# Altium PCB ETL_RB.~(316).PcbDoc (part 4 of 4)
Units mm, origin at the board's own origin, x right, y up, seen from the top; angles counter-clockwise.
Board outline 130.3 x 56.5 mm, 8 copper layers (Top Layer, plane 1, M1, plane 2, plane 3, M2, plane 4, Bottom Layer), stack 0.972 mm thick; 202 components, 189 nets, 1825 pads, 884 vias.
Unrouted connection lines stored in the file: 411.

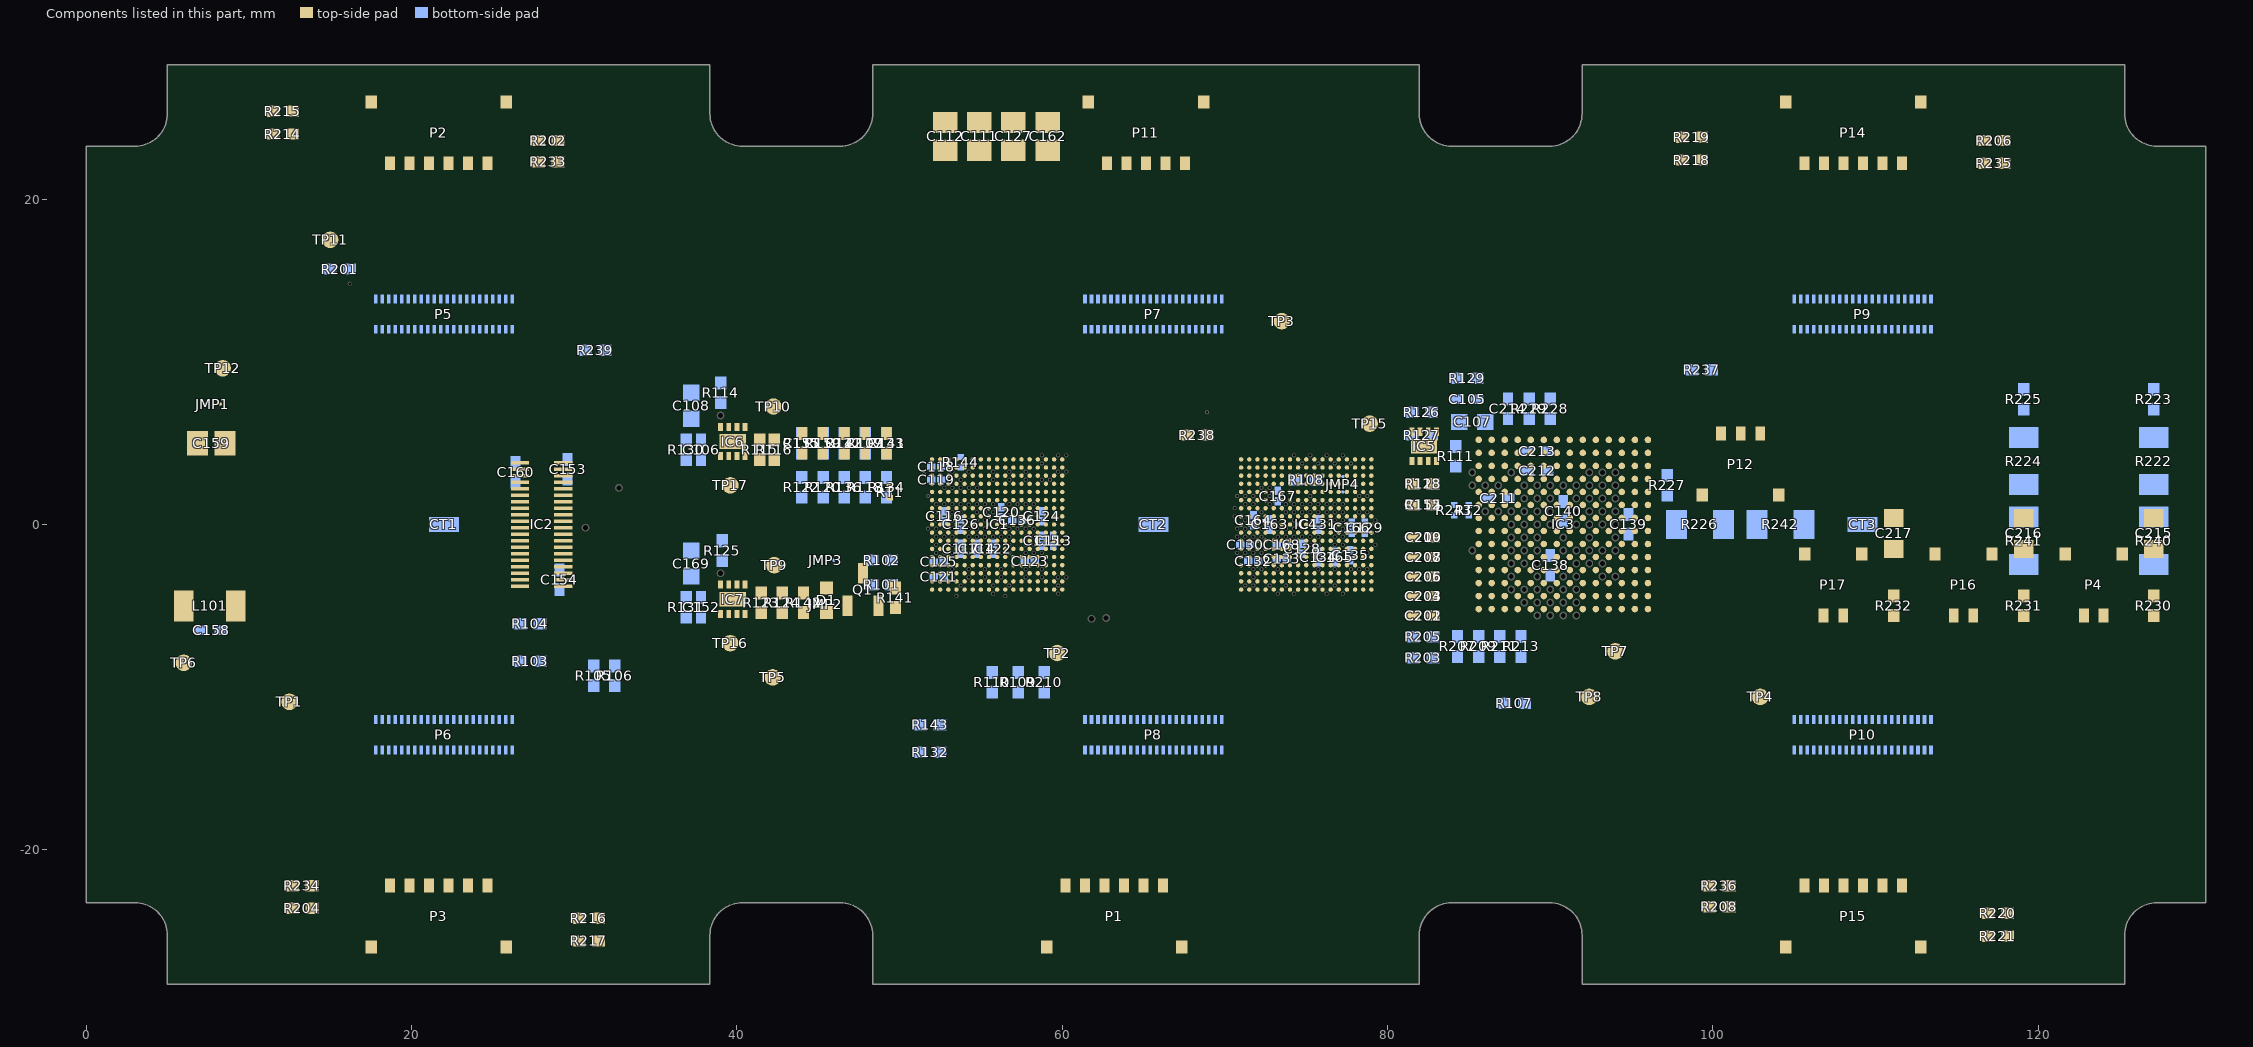
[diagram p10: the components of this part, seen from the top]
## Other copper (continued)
plane 2 (plane layer: these items are gaps in the copper):
  lines w0.152: 70.8,28.3 70.8,14.9 67.9,12 62.9,12 62.9,8.7 ; 89.6,-3.6 86.8,-3.6 86,-2.8 86,0.5 80,0.5 80,3.8 80,7 95.2,7 95.2,-4.4 92,-4.4 ; 109.7,-28.3 109.7,-27.5 109.7,-12.7 105.2,-12.7 101.7,-12.7 101.7,5.8 107.7,11.8 111.2,11.8 ; 130.3,7 111.2,7 111.2,11.8 ; 4.2,-8.4 4.2,-12.5 14.7,-23 32.1,-23 35.422,-19.678 72.878,-19.678 72.878,-9.122 61.1,-9.122 61.1,-10.8 63.8,-13.5 65.4,-13.5 65.4,-15.9 17.9,-15.9 17.3,-15.3 17.3,-14.4 20,-11.7 ; 4.2,-8.4 20,-8.4 20,-11.7 ; 4.2,-8.4 4.2,18.1 9.8,23.7 22.2,23.7 22.2,14.2 23.8,12.6 29.4,12.6 29.4,8 11.5,8 11.5,-4.8 24,-4.8 24,-11.7 20,-11.7 ; 62.9,8.7 62.9,8.7 ; 62.9,8.7 72.9,8.7 80.2,16 113.7,16 113.7,14.3 111.2,11.8 ; 92,-4.4 89.6,-4.4 89.6,-2 89.6,2.8 83.8,2.8 82.5,4.1 82.5,5.3 92,5.3 92,-4.4

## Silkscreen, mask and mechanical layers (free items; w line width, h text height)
Mechanical 1:
  the board outline again, w0.15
